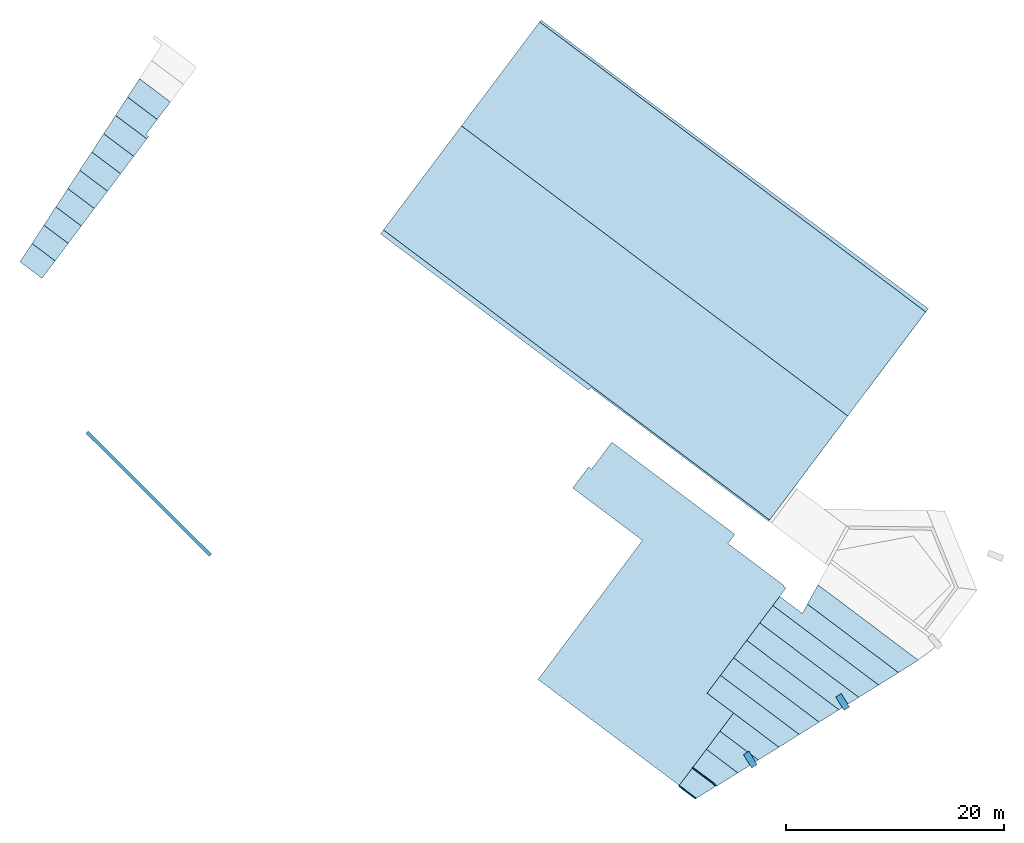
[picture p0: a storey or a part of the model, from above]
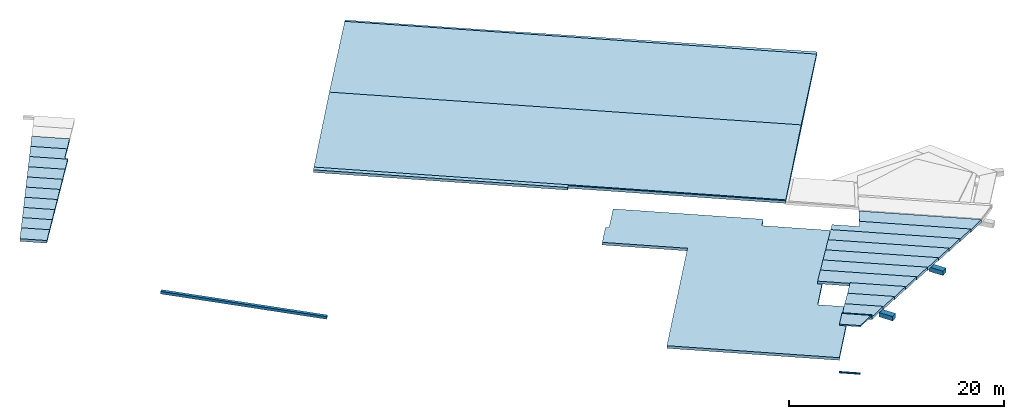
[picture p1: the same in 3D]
Properties of the parts of a building model (IFC2X3)

# File
Description: ViewDefinition [CoordinationView_V2.0], RevitIdentifiers [VersionGUID: fc82f88f-a926-4ae7-b725-2671d25d69d6, NumberOfSaves: 167], CoordinateReference [CoordinateBase: Coordenadas compartidas, ProjectSite: Interna]
File name: 0001
Time: 2024-03-04T15:58:45
Written by: ODA IFC SDK 22.8
Made in: 22.1.50.17 - Exporter 22.6.2.0 - IU alternativa 22.6.2.0

# IfcProject, 0001
LongName: TÍTOL DEL PROJECTE; Phase: Estado de proyecto

# IfcSite, Superficie:112586
RefLatitude: 40, 24, 0, 5493; RefLongitude: -3, -40, -59, -880065; RefElevation: 0 m

# IfcBuilding
Pset_BuildingCommon - NumberOfStoreys: 4

# IfcBuildingStorey: Nivel:A- Nivell (4)
Name | LongName | Elevation (m)
PS1- Gimnàs | PS1- Gimnàs | -5.45
PS1- Vestuari | PS1- Vestuari | -4.46
P0- Escola | P0- Escola | 0
PC- Coberta STR | PC- Coberta STR | 3.4

# IfcBuildingElementProxy: PerfilVoltant:PerfilVoltant (2)
In: P0- Escola
Type - Material: <Unnamed>
Pset_BuildingElementProxyCommon - Reference: PerfilVoltant; sets with these values: 2
Name (PerfilVoltant:PerfilVoltant:...)
849642
887236

# IfcColumn: STR- P- Acer- RHS- Rectangular- T1:45 x 25RHS (7)
In: P0- Escola
Type - PredefinedType: COLUMN; Material: Metal - Acero - 345 MPa
Type - Pset_ColumnCommon - IsExternal: no; LoadBearing: yes
Pset_ColumnCommon - Reference: 45 x 25RHS
Pset_QuantityTakeOff - Reference: 45 x 25RHS; sets with these values: 2
Name (STR- P- Acer- RHS- Rectangular- T1:45 x 25RHS:...)
849639
849651
849653
849655
886750
886810
886834

# IfcCurtainWall: Muro cortina:SER EXT- Tanca exterior (46)
Type - Pset_CurtainWallCommon - IsExternal: yes
Pset_CurtainWallCommon - Reference: SER EXT- Tanca exterior
Pset_QuantityTakeOff - Reference: SER EXT- Tanca exterior
Name (Muro cortina:SER EXT- Tanca exterior:...) | In
178892 | P0- Escola
178897 | P0- Escola
178907 | P0- Escola
178912 | P0- Escola
219770 | P0- Escola
220218 | P0- Escola
220369 | P0- Escola
220476 | P0- Escola
220625 | P0- Escola
220727 | P0- Escola
220855 | P0- Escola
220986 | P0- Escola
221199 | P0- Escola
221353 | P0- Escola
221500 | P0- Escola
221639 | P0- Escola
221781 | P0- Escola
221917 | P0- Escola
222063 | P0- Escola
222252 | P0- Escola
222425 | P0- Escola
222799 | PC- Coberta STR
222915 | PC- Coberta STR
223154 | PC- Coberta STR
223494 | P0- Escola
223676 | P0- Escola
223843 | P0- Escola
223951 | P0- Escola
224065 | P0- Escola
224211 | P0- Escola
224432 | PC- Coberta STR
226283 | PS1- Vestuari
226287 | PS1- Vestuari
226291 | PS1- Vestuari
226295 | PS1- Vestuari
226299 | PS1- Vestuari
226303 | PS1- Vestuari
226307 | PS1- Vestuari
226311 | PS1- Vestuari
226315 | PS1- Vestuari
242768 | PC- Coberta STR
243418 | PC- Coberta STR
243803 | PC- Coberta STR
249298 | P0- Escola
258339 | PS1- Vestuari
825201 | P0- Escola

# IfcDoor: SER EXT- SG2- Abatible- Ext:SER- EXT- SG2- Abatible- Ext- 1.98m (2)
In: PS1- Vestuari
Type - ParameterTakesPrecedence: no; Sizeable: no; Material: <Unnamed>
Type - Pset_DoorCommon - IsExternal: no
OverallHeight: 5.045 m; OverallWidth: 1.2275 m
Pset_DoorCommon - Reference: SER- EXT- SG2- Abatible- Ext- 1.98m
Pset_QuantityTakeOff - Reference: SER- EXT- SG2- Abatible- Ext- 1.98m
Name (SER EXT- SG2- Abatible- Ext:SER- EXT- SG2- Abatible- Ext- 1.98m:...)
884023
971733

# IfcDoor: SER EXT- SG2- Abatible- Ext:SER- EXT- SG2- Abatible- Ext- 2.15m, SER EXT- SG2- Abatible- Ext:SER- EXT- SG2- Abatible- Ext- 2.15m:849643
In: PS1- Vestuari
Type - ParameterTakesPrecedence: no; Sizeable: no; Material: <Unnamed>
Type - Pset_DoorCommon - IsExternal: no
OverallHeight: 5.215 m; OverallWidth: 1.42 m
Pset_DoorCommon - Reference: SER- EXT- SG2- Abatible- Ext- 2.15m
Pset_QuantityTakeOff - Reference: SER- EXT- SG2- Abatible- Ext- 2.15m

# IfcDoor: SER EXT- SG2- Abatible- Int:SER- EXT- SG2- Abatible ext - 1.98m (2)
In: P0- Escola
Type - ParameterTakesPrecedence: no; Sizeable: no; Material: <Unnamed>
Type - Pset_DoorCommon - IsExternal: no
OverallHeight: 5.63 m; OverallWidth: 1.1575 m
Pset_DoorCommon - Reference: SER- EXT- SG2- Abatible ext - 1.98m
Pset_QuantityTakeOff - Reference: SER- EXT- SG2- Abatible ext - 1.98m
Name (SER EXT- SG2- Abatible- Int:SER- EXT- SG2- Abatible ext - 1.98m:...)
877908
971731

# IfcDoor: SER EXT- SG2- Abatible- Int:SER- EXT- SG2- Abatible ext 2.15m, SER EXT- SG2- Abatible- Int:SER- EXT- SG2- Abatible ext 2.15m:849644
In: PS1- Vestuari
Type - ParameterTakesPrecedence: no; Sizeable: no; Material: <Unnamed>
Type - Pset_DoorCommon - IsExternal: no
OverallHeight: 5.8 m; OverallWidth: 1.35 m
Pset_DoorCommon - Reference: SER- EXT- SG2- Abatible ext 2.15m
Pset_QuantityTakeOff - Reference: SER- EXT- SG2- Abatible ext 2.15m

# IfcDoor: SER EXT- SG2- FIXE:SER- EXT- SG2- FIXE- 2.15m (2)
In: PS1- Vestuari
Type - ParameterTakesPrecedence: no; Sizeable: no; Material: <Unnamed>
Type - Pset_DoorCommon - IsExternal: no
OverallHeight: 2.14 m
Pset_DoorCommon - Reference: SER- EXT- SG2- FIXE- 2.15m
Pset_QuantityTakeOff - Reference: SER- EXT- SG2- FIXE- 2.15m
Name (SER EXT- SG2- FIXE:SER- EXT- SG2- FIXE- 2.15m:...) | OverallWidth (m)
849638 | 1
849650 | 1.024

# IfcDoor: SER URB- SM1a- PORTA ACCES ESCOLA:SER URB- SM1a- PORTA ACCES ESCOLA, SER URB- SM1a- PORTA ACCES ESCOLA:SER URB- SM1a- PORTA ACCES ESCOLA:906945
In: P0- Escola
Type - ParameterTakesPrecedence: no; Sizeable: no; Material: <Unnamed>
Type - Pset_DoorCommon - IsExternal: no
OverallHeight: 5.1 m; OverallWidth: 5.04225 m
Pset_DoorCommon - IsExternal: yes; Reference: SER URB- SM1a- PORTA ACCES ESCOLA
Pset_QuantityTakeOff - Reference: SER URB- SM1a- PORTA ACCES ESCOLA

# IfcDoor: SER URB- SM1b- FIXE OPACA:SER URB- SM1b- FIXE OPACA, SER URB- SM1b- FIXE OPACA:SER URB- SM1b- FIXE OPACA:909046
In: P0- Escola
Type - ParameterTakesPrecedence: no; Sizeable: no; Material: <Unnamed>
Type - Pset_DoorCommon - IsExternal: no
OverallHeight: 5 m; OverallWidth: 0.405 m
Pset_DoorCommon - IsExternal: yes; Reference: SER URB- SM1b- FIXE OPACA
Pset_QuantityTakeOff - Reference: SER URB- SM1b- FIXE OPACA

# IfcDoor: SER URB- SM1b- PORTA PETITA ACCES ESCOLA:SER URB- SM1b- PORTA PETITA ACCES ESCOLA, SER URB- SM1b- PORTA PETITA ACCES ESCOLA:SER URB- SM1b- PORTA PETITA ACCES ESCOLA:911182
In: PS1- Vestuari
Type - ParameterTakesPrecedence: no; Sizeable: no; Material: <Unnamed>
Type - Pset_DoorCommon - IsExternal: no
OverallHeight: 5 m; OverallWidth: 1.32329 m
Pset_DoorCommon - IsExternal: yes; Reference: SER URB- SM1b- PORTA PETITA ACCES ESCOLA
Pset_QuantityTakeOff - Reference: SER URB- SM1b- PORTA PETITA ACCES ESCOLA

# IfcDoor: SER URB- SM3- PORTA ACCES ESCOLA INFERIOR:SER URB- SM3- PORTA ACCES ESCOLA INFERIOR, SER URB- SM3- PORTA ACCES ESCOLA INFERIOR:SER URB- SM3- PORTA ACCES ESCOLA INFERIOR:841666
In: P0- Escola
Type - ParameterTakesPrecedence: no; Sizeable: no; Material: <Unnamed>
Type - Pset_DoorCommon - IsExternal: no
OverallHeight: 4.95 m; OverallWidth: 5.04225 m
Pset_DoorCommon - Reference: SER URB- SM3- PORTA ACCES ESCOLA INFERIOR
Pset_QuantityTakeOff - Reference: SER URB- SM3- PORTA ACCES ESCOLA INFERIOR

# IfcMember: Montante circular:Perfil Tanca exterior (158)
Type - PredefinedType: MULLION; Material: Acero inoxidable
Type - Pset_MemberCommon - IsExternal: no
Pset_MemberCommon - Reference: Perfil Tanca exterior
Pset_QuantityTakeOff - Reference: Perfil Tanca exterior
Name (Montante circular:Perfil Tanca exterior:...) | In | Span (m)
218592 | P0- Escola | 2 | Pset_MemberCommon - IsExternal: yes
224694 | P0- Escola | 2 | Pset_MemberCommon - IsExternal: yes
246355 | P0- Escola | 2 | Pset_MemberCommon - IsExternal: yes
213103 | P0- Escola | 2.01067
213405 | P0- Escola | 2.01067
213406 | P0- Escola | 1.95
213432 | P0- Escola | 2.01188
213433 | P0- Escola | 1.95
213464 | P0- Escola | 2.01188
213465 | P0- Escola | 1.95
213486 | P0- Escola | 2.01024
213487 | P0- Escola | 1.95
224695 | P0- Escola | 1.95
246356 | P0- Escola | 2
226271 | P0- Escola | 2
246358 | P0- Escola | 2
226239 | P0- Escola | 2
226240 | P0- Escola | 2
226241 | P0- Escola | 2
226242 | P0- Escola | 2
226243 | P0- Escola | 2
226244 | P0- Escola | 2
226245 | P0- Escola | 2
219928 | P0- Escola | 2
224699 | P0- Escola | 2
246362 | P0- Escola | 2
224700 | P0- Escola | 2
226535 | P0- Escola | 2
246363 | P0- Escola | 2.05
224701 | P0- Escola | 2
226584 | P0- Escola | 2
246364 | P0- Escola | 2
224702 | P0- Escola | 2
226633 | P0- Escola | 2
246365 | P0- Escola | 2
224703 | P0- Escola | 2
226698 | P0- Escola | 2
246366 | P0- Escola | 2
224704 | P0- Escola | 2
226775 | P0- Escola | 2
246367 | P0- Escola | 2.05
224705 | P0- Escola | 2
226870 | P0- Escola | 2
224706 | P0- Escola | 2
226957 | P0- Escola | 2
246369 | P0- Escola | 2.05
224707 | P0- Escola | 2
227058 | P0- Escola | 2
246370 | P0- Escola | 2.05
224708 | P0- Escola | 2
227159 | P0- Escola | 2
246371 | P0- Escola | 2.05
224709 | P0- Escola | 2
227236 | P0- Escola | 2
246372 | P0- Escola | 2.05
224710 | P0- Escola | 2
227293 | P0- Escola | 2
246373 | P0- Escola | 2.05
224711 | P0- Escola | 2
227364 | P0- Escola | 2
246374 | P0- Escola | 2.05
224712 | P0- Escola | 2
227481 | P0- Escola | 2
246375 | P0- Escola | 2.05
224713 | P0- Escola | 2
227568 | P0- Escola | 2
246376 | P0- Escola | 2.05
224714 | P0- Escola | 2
227621 | P0- Escola | 2
246377 | P0- Escola | 2.05
224715 | P0- Escola | 2
227748 | P0- Escola | 2
246378 | P0- Escola | 2
224716 | PC- Coberta STR | 2.05
225268 | PC- Coberta STR | 2
246379 | PC- Coberta STR | 2
224717 | PC- Coberta STR | 2.05
225345 | PC- Coberta STR | 2
246380 | PC- Coberta STR | 2
224718 | PC- Coberta STR | 2.05
225448 | PC- Coberta STR | 2
246381 | PC- Coberta STR | 2
224719 | P0- Escola | 2
225774 | P0- Escola | 2
246382 | P0- Escola | 2
224720 | P0- Escola | 2.05
225825 | P0- Escola | 2
246383 | P0- Escola | 2
224721 | P0- Escola | 2.05
225894 | P0- Escola | 2
246384 | P0- Escola | 2
224722 | P0- Escola | 2.05
225967 | P0- Escola | 2
246385 | P0- Escola | 2
224723 | P0- Escola | 2.05
226010 | P0- Escola | 2
246386 | P0- Escola | 2
224724 | P0- Escola | 2.05
226113 | P0- Escola | 2
226152 | P0- Escola | 2
246387 | P0- Escola | 2
224874 | PC- Coberta STR | 2
225174 | PC- Coberta STR | 2
830094 | PC- Coberta STR | 2
260684 | PS1- Vestuari | 2
260866 | PS1- Vestuari | 2
260974 | PS1- Vestuari | 2
261100 | PS1- Vestuari | 2
261216 | PS1- Vestuari | 2
261318 | PS1- Vestuari | 2
261446 | PS1- Vestuari | 2
261809 | PS1- Vestuari | 2
262452 | PS1- Vestuari | 2
259919 | PS1- Vestuari | 2
260018 | PS1- Vestuari | 2
260059 | PS1- Vestuari | 2
260165 | PS1- Vestuari | 2
260259 | PS1- Vestuari | 2
260317 | PS1- Vestuari | 2
260550 | PS1- Vestuari | 2
226432 | PS1- Vestuari | 2
259739 | PS1- Vestuari | 2
261954 | PS1- Vestuari | 2
226433 | PS1- Vestuari | 2.05
259070 | PS1- Vestuari | 2
259186 | PS1- Vestuari | 2
259493 | PS1- Vestuari | 2
259601 | PS1- Vestuari | 2
226434 | PS1- Vestuari | 2
246392 | PS1- Vestuari | 2.05
226435 | PS1- Vestuari | 2.05
258709 | PS1- Vestuari | 2
258770 | PS1- Vestuari | 2
226436 | PS1- Vestuari | 2
246394 | PS1- Vestuari | 2
226437 | PS1- Vestuari | 2
242773 | PC- Coberta STR | 2
244245 | PC- Coberta STR | 2
244415 | PC- Coberta STR | 2
246397 | PC- Coberta STR | 2
243421 | PC- Coberta STR | 2.05
244627 | PC- Coberta STR | 2
244905 | PC- Coberta STR | 2
245248 | PC- Coberta STR | 2
245395 | PC- Coberta STR | 2
246398 | PC- Coberta STR | 2
243806 | PC- Coberta STR | 2.05
245706 | PC- Coberta STR | 2
245858 | PC- Coberta STR | 2
246123 | PC- Coberta STR | 2
249302 | P0- Escola | 2
249303 | P0- Escola | 2
249627 | P0- Escola | 2
249694 | P0- Escola | 2
258342 | PS1- Vestuari | 2
258343 | PS1- Vestuari | 2
825320 | P0- Escola | 2
825321 | P0- Escola | 2.05

# IfcMember: Montante rectangular:Montante rectangular 100x50 (121)
Type - PredefinedType: MULLION; Material: _Formigó- Solera- T1- STR
Type - Pset_MemberCommon - IsExternal: no
Pset_MemberCommon - Reference: Montante rectangular 100x50
Pset_QuantityTakeOff - Reference: Montante rectangular 100x50
Name (Montante rectangular:Montante rectangular 100x50:...) | In | Span (m)
794372 | P0- Escola | 1.08514 | Pset_MemberCommon - IsExternal: yes
794373 | P0- Escola | 2.21752 | Pset_MemberCommon - IsExternal: yes
794374 | P0- Escola | 1.96448
794375 | P0- Escola | 2.01454
794376 | P0- Escola | 2.01454
794377 | P0- Escola | 2.0129
794378 | P0- Escola | 2.012
794380 | P0- Escola | 2.03155
794381 | P0- Escola | 1.98418
794382 | P0- Escola | 1.98668
794383 | P0- Escola | 1.98668
794384 | P0- Escola | 1.98668
794385 | P0- Escola | 1.98668
794386 | P0- Escola | 1.98668
794387 | P0- Escola | 1.98644
794388 | P0- Escola | 1.60597
794389 | P0- Escola | 2
794390 | P0- Escola | 2.05
794391 | P0- Escola | 1.95
794392 | P0- Escola | 2.05
794393 | P0- Escola | 2
794394 | P0- Escola | 2.05
794395 | P0- Escola | 2
794396 | P0- Escola | 2.05
794397 | P0- Escola | 2
794398 | P0- Escola | 2.05
794399 | P0- Escola | 1.95
794400 | P0- Escola | 2
794401 | P0- Escola | 2
794402 | P0- Escola | 2.05
794403 | P0- Escola | 1.95
794404 | P0- Escola | 2.05
794405 | P0- Escola | 1.95
794406 | P0- Escola | 2.05
794407 | P0- Escola | 1.95
794408 | P0- Escola | 2.05
794409 | P0- Escola | 1.95
794410 | P0- Escola | 2.05
794411 | P0- Escola | 1.95
794412 | P0- Escola | 2.05
794413 | P0- Escola | 1.95
794414 | P0- Escola | 2.05
794415 | P0- Escola | 1.95
794416 | P0- Escola | 2.05
794417 | P0- Escola | 1.95
794418 | P0- Escola | 2.05
794419 | P0- Escola | 1.95
794420 | P0- Escola | 2.05
794421 | P0- Escola | 3.18127
794422 | P0- Escola | 2.05
794423 | PC- Coberta STR | 2.05
794424 | PC- Coberta STR | 1.95
794425 | PC- Coberta STR | 2.05
794426 | PC- Coberta STR | 1.95
794427 | PC- Coberta STR | 2
794428 | PC- Coberta STR | 1.95
794429 | P0- Escola | 2.05
794430 | P0- Escola | 2
794431 | P0- Escola | 2.05
794432 | P0- Escola | 1.95
794433 | P0- Escola | 2.05
794434 | P0- Escola | 1.95
794435 | P0- Escola | 2.05
794436 | P0- Escola | 1.95
794437 | P0- Escola | 2.05
794438 | P0- Escola | 1.95
794439 | P0- Escola | 2
794440 | P0- Escola | 1.95
794441 | P0- Escola | 2
794442 | PC- Coberta STR | 2.42351
794443 | PC- Coberta STR | 2.05
794444 | PS1- Vestuari | 0.381107
794445 | PS1- Vestuari | 0.350019
794446 | PS1- Vestuari | 2
794447 | PS1- Vestuari | 2
794448 | PS1- Vestuari | 2
794449 | PS1- Vestuari | 2
794450 | PS1- Vestuari | 2
794451 | PS1- Vestuari | 2
794452 | PS1- Vestuari | 2
794453 | PS1- Vestuari | 1.89214
794454 | PS1- Vestuari | 1.64287
794455 | PS1- Vestuari | 1.30014
794456 | PS1- Vestuari | 2
794457 | PS1- Vestuari | 2
794458 | PS1- Vestuari | 2
794459 | PS1- Vestuari | 2
794460 | PS1- Vestuari | 2
794461 | PS1- Vestuari | 2
794462 | PS1- Vestuari | 0.724806
794463 | PS1- Vestuari | 2
794464 | PS1- Vestuari | 2
794465 | PS1- Vestuari | 2.00295
794466 | PS1- Vestuari | 1.95
794467 | PS1- Vestuari | 2
794468 | PS1- Vestuari | 2
794469 | PS1- Vestuari | 2
794470 | PS1- Vestuari | 1.95034
794471 | PS1- Vestuari | 2.00034
794472 | PS1- Vestuari | 1.95
794473 | PS1- Vestuari | 2.0277
794474 | PS1- Vestuari | 2.00665
794475 | PS1- Vestuari | 2
794476 | PS1- Vestuari | 2
794477 | PC- Coberta STR | 2.00218
794478 | PC- Coberta STR | 2.05
794479 | PC- Coberta STR | 2
794480 | PC- Coberta STR | 2.02451
794481 | PC- Coberta STR | 1.95
794482 | PC- Coberta STR | 2
794483 | PC- Coberta STR | 2
794484 | PC- Coberta STR | 2
794485 | PC- Coberta STR | 0.975363
794486 | PC- Coberta STR | 1.95
794487 | PC- Coberta STR | 2
794488 | PC- Coberta STR | 2
794489 | P0- Escola | 2.0155
794490 | P0- Escola | 2.0155
794491 | P0- Escola | 2.02639
794493 | PS1- Vestuari | 2.03879
825319 | P0- Escola | 1.61378

# IfcRailing: Barandilla:BaranaEscalaBiblioteca_NomesBarana (3)
In: P0- Escola
Material: <Unnamed>
Pset_QuantityTakeOff - Reference: BaranaEscalaBiblioteca_NomesBarana
Pset_RailingCommon - IsExternal: no; Reference: BaranaEscalaBiblioteca_NomesBarana; Height: 0.81 m
Name (Barandilla:BaranaEscalaBiblioteca_NomesBarana:...)
417718
427256
427480

# IfcRailing: Barandilla:BaranaEscalaGimnas, Barandilla:BaranaEscalaGimnas:429829
In: P0- Escola
Material: <Unnamed>
Pset_QuantityTakeOff - Reference: BaranaEscalaGimnas
Pset_RailingCommon - IsExternal: no; Reference: BaranaEscalaGimnas; Height: 0.81 m

# IfcRailing: Barandilla:PassamansDoble_sWa1, Barandilla:PassamansDoble_sWa1:433244
In: P0- Escola
Material: <Unnamed>
Pset_QuantityTakeOff - Reference: PassamansDoble_sWa1
Pset_RailingCommon - IsExternal: no; Reference: PassamansDoble_sWa1; Height: 0.81 m

# IfcRailing: Barandilla:SER EXT- Barana biblioteca, Barandilla:SER EXT- Barana biblioteca:429284
In: P0- Escola
Material: <Unnamed>
Pset_QuantityTakeOff - Reference: SER EXT- Barana biblioteca
Pset_RailingCommon - IsExternal: no; Reference: SER EXT- Barana biblioteca; Height: 0.81 m

# IfcRailing: Barandilla:SER EXT- Barana pati infantil, Barandilla:SER EXT- Barana pati infantil:429043
In: P0- Escola
Material: <Unnamed>
Pset_QuantityTakeOff - Reference: SER EXT- Barana pati infantil
Pset_RailingCommon - IsExternal: no; Reference: SER EXT- Barana pati infantil; Height: 0.81 m

# IfcRailing: SER URB- SM1d- TANCA LATERAL GRAN:SER URB- SM1d- TANCA LATERAL GRAN, SER URB- SM1d- TANCA LATERAL GRAN:SER URB- SM1d- TANCA LATERAL GRAN:915583
In: P0- Escola
Type - Material: <Unnamed>
Type - Pset_RailingCommon - IsExternal: no
Pset_QuantityTakeOff - Reference: SER URB- SM1d- TANCA LATERAL GRAN
Pset_RailingCommon - IsExternal: yes; Reference: SER URB- SM1d- TANCA LATERAL GRAN

# IfcRailing: SER URB- SM1d- TANCA LATERAL PETITA CANTONADA:SER URB- SM1d- TANCA LATERAL PETITA CANTONADA, SER URB- SM1d- TANCA LATERAL PETITA CANTONADA:SER URB- SM1d- TANCA LATERAL PETITA CANTONADA:912986
In: P0- Escola
Type - Material: <Unnamed>
Type - Pset_RailingCommon - IsExternal: no
Pset_QuantityTakeOff - Reference: SER URB- SM1d- TANCA LATERAL PETITA CANTONADA
Pset_RailingCommon - IsExternal: yes; Reference: SER URB- SM1d- TANCA LATERAL PETITA CANTONADA

# IfcRoof: Cubierta básica:COB- Coberta Xapa 2 (2)
In: P0- Escola
Material: _REV- Xapa minionda 0.01 m, _Genèric perfils, muntants, rastrells 0.01 m, _Aillament 0.08 m
Pset_QuantityTakeOff - Reference: COB- Coberta Xapa 2
Pset_RoofCommon - IsExternal: yes; Reference: COB- Coberta Xapa 2
Name (Cubierta básica:COB- Coberta Xapa 2:...) | ProjectedArea (m2) | TotalArea (m2)
902991 | 6.10059 | 6.11156
903251 | 6.13022 | 6.14125

# IfcRoof: Cubierta básica:COB- Coberta Xapa Exterior, Cubierta básica:COB- Coberta Xapa Exterior:886697
In: P0- Escola
Material: _REV- Xapa minionda 0.01 m, _Genèric perfils, muntants, rastrells 0.01 m, _Aillament 0.04 m
Pset_QuantityTakeOff - Reference: COB- Coberta Xapa Exterior
Pset_RoofCommon - IsExternal: yes; Reference: COB- Coberta Xapa Exterior; ProjectedArea: 3.40161 m2; TotalArea: 3.40161 m2

# IfcSlab: Cubierta básica:COB- Coberta Xapa 2 (2)
In: P0- Escola
Type - PredefinedType: ROOF
Type - Pset_SlabCommon - IsExternal: yes; ThermalTransmittance: 2.49973 kg/K/s3
Material: _REV- Xapa minionda 0.01 m, _Genèric perfils, muntants, rastrells 0.01 m, _Aillament 0.08 m
Pset_QuantityTakeOff - Reference: COB- Coberta Xapa 2; sets with these values: 2
Pset_SlabCommon - Reference: COB- Coberta Xapa 2; PitchAngle: 3.43363 deg
Name (Cubierta básica:COB- Coberta Xapa 2:...)
902991
903251

# IfcSlab: Cubierta básica:COB- Coberta Xapa Exterior, Cubierta básica:COB- Coberta Xapa Exterior:886697
In: P0- Escola
Type - PredefinedType: ROOF
Type - Pset_SlabCommon - IsExternal: yes; ThermalTransmittance: 2.49973 kg/K/s3
Material: _REV- Xapa minionda 0.01 m, _Genèric perfils, muntants, rastrells 0.01 m, _Aillament 0.04 m
Pset_QuantityTakeOff - Reference: COB- Coberta Xapa Exterior; sets with these values: 2
Pset_SlabCommon - PitchAngle: 0 deg; Reference: COB- Coberta Xapa Exterior

# IfcSlab: Plataforma:300 mm (110)
Type - PredefinedType: FLOOR; Material: _Topografia- Plataformes 0.3 m
Type - Pset_SlabCommon - IsExternal: no; ThermalTransmittance: 2.79 kg/K/s3
Pset_QuantityTakeOff - Reference: 300 mm; sets with these values: 2
Pset_SlabCommon - Reference: 300 mm
Name (Plataforma:300 mm:...) | In | PitchAngle (deg)
112604 | PS1- Gimnàs | 0
112612 | PS1- Vestuari | 0
112616 | PS1- Gimnàs | 0
112622 | PS1- Gimnàs | 1.14576
112626 | PS1- Vestuari | 0
112634 | PS1- Vestuari | 0
112641 | PS1- Vestuari | 3.75745
112661 | PS1- Vestuari | 5.10682
112667 | PS1- Vestuari | 0
112715 | P0- Escola | 4.57392
112724 | PS1- Gimnàs | 4.57392
112733 | PS1- Gimnàs | 4.57392
112742 | PS1- Gimnàs | 4.57392
112751 | PS1- Gimnàs | 4.57392
112760 | PS1- Gimnàs | 4.57392
112769 | PS1- Gimnàs | 4.57392
112778 | PS1- Gimnàs | 4.57392
112787 | PS1- Gimnàs | 4.57392
112798 | PS1- Gimnàs | 4.57392
112951 | PS1- Gimnàs | 1.14576
112959 | PS1- Gimnàs | 4.57392
113110 | PS1- Vestuari | 0
113144 | PS1- Gimnàs | 1.14576
113154 | PS1- Gimnàs | 0
113319 | PS1- Gimnàs | 2.29061
113327 | PS1- Gimnàs | 2.29061
113335 | PS1- Gimnàs | 2.29061
113634 | PS1- Gimnàs | 4.57392
113643 | PS1- Gimnàs | 4.57392
113651 | PS1- Gimnàs | 4.57392
113658 | PS1- Gimnàs | 4.57392
113665 | PS1- Gimnàs | 4.57392
113672 | PS1- Gimnàs | 4.57392
113680 | PS1- Gimnàs | 4.57392
113688 | PS1- Gimnàs | 4.57392
113696 | PS1- Gimnàs | 4.57392
113704 | PS1- Gimnàs | 4.57392
113711 | PS1- Gimnàs | 4.57392
113719 | PS1- Gimnàs | 4.57392
113879 | PS1- Vestuari | 4.57392
113892 | PS1- Vestuari | 4.57392
113901 | PS1- Vestuari | 4.57392
113910 | PS1- Vestuari | 4.57392
113919 | PS1- Vestuari | 4.57392
113941 | P0- Escola | 0
113957 | P0- Escola | 0
113968 | P0- Escola | 0
114032 | PS1- Vestuari | 0
114047 | P0- Escola | 7.32777
114102 | P0- Escola | 1.43206
114382 | P0- Escola | 0
114419 | P0- Escola | 0
114427 | PS1- Vestuari | 0
114435 | P0- Escola | 0
114444 | P0- Escola | 0
114452 | P0- Escola | 0
114487 | PS1- Vestuari | 4.57361
114496 | PS1- Vestuari | 4.57392
114505 | PS1- Vestuari | 0.859372
114513 | PS1- Vestuari | 1.14576
114530 | PS1- Vestuari | 0
114538 | PS1- Vestuari | 25.5005
114556 | PS1- Vestuari | 0
114567 | PS1- Vestuari | 0
114583 | PS1- Vestuari | 0
114600 | PS1- Vestuari | 0
114621 | PS1- Vestuari | 0
114629 | PS1- Vestuari | 25.4496
114638 | PS1- Vestuari | 25.8881
114647 | PS1- Vestuari | 0
114655 | PS1- Vestuari | 25.8881
114664 | PS1- Vestuari | 0
114672 | P0- Escola | 0
114680 | P0- Escola | 0
114688 | P0- Escola | 0
114696 | P0- Escola | 0
429259 | P0- Escola | 0
433192 | PS1- Gimnàs | 0
436202 | P0- Escola | 0
437801 | P0- Escola | 0
437916 | P0- Escola | 0
438030 | P0- Escola | 0
438046 | P0- Escola | 0
438072 | P0- Escola | 0
438098 | P0- Escola | 0
438118 | P0- Escola | 0
438151 | P0- Escola | 0
438417 | PS1- Gimnàs | 0
438637 | PS1- Vestuari | 0
440489 | PS1- Vestuari | 0
622989 | P0- Escola | 0
623017 | P0- Escola | 0
623747 | P0- Escola | 1.08092
623801 | P0- Escola | 1.78991
624366 | P0- Escola | 0
624937 | P0- Escola | 1.78991
625013 | P0- Escola | 1.08092
625038 | P0- Escola | 0
625057 | P0- Escola | 1.78991
625118 | P0- Escola | 1.08092
625294 | P0- Escola | 0
625413 | P0- Escola | 1.34789
626050 | P0- Escola | 1.34789
626185 | P0- Escola | 0
627149 | P0- Escola | 0
628680 | P0- Escola | 4.01039
812884 | P0- Escola | 4.49797
813592 | P0- Escola | 2.32091
847177 | P0- Escola | 0
953251 | P0- Escola | 3.00519

# IfcSlab: STR- S- Formigó- Mp5:STR- S- Formigó- Mp5, STR- S- Formigó- Mp5:STR- S- Formigó- Mp5:119742
In: PS1- Vestuari
Type - PredefinedType: BASESLAB; Material: _Formigó- T1- STR
Type - Pset_SlabCommon - IsExternal: no
Pset_QuantityTakeOff - Reference: STR- S- Formigó- Mp5; sets with these values: 2
Pset_SlabCommon - Reference: STR- S- Formigó- Mp5

# IfcSlab: STR- Sabata- Unio sabata MP1:STR- Sabata- Unio sabata MP1, STR- Sabata- Unio sabata MP1:STR- Sabata- Unio sabata MP1:119833
In: PS1- Vestuari
Type - PredefinedType: BASESLAB; Material: _Formigó- T1- STR
Type - Pset_SlabCommon - IsExternal: no
Pset_QuantityTakeOff - Reference: STR- Sabata- Unio sabata MP1; sets with these values: 2
Pset_SlabCommon - Reference: STR- Sabata- Unio sabata MP1

# IfcSlab: STR- Sabata- Unio sabata MP2:STR- Sabata- Unio sabata MP1, STR- Sabata- Unio sabata MP2:STR- Sabata- Unio sabata MP1:119843
In: PS1- Gimnàs
Type - PredefinedType: BASESLAB; Material: _Formigó- T1- STR
Type - Pset_SlabCommon - IsExternal: no
Pset_QuantityTakeOff - Reference: STR- Sabata- Unio sabata MP1; sets with these values: 2
Pset_SlabCommon - Reference: STR- Sabata- Unio sabata MP1

# IfcSlab: STR- Sabata- Unio sabata MP3:STR- Sabata- Unio sabata MP1, STR- Sabata- Unio sabata MP3:STR- Sabata- Unio sabata MP1:119851
In: PS1- Gimnàs
Type - PredefinedType: BASESLAB; Material: _Formigó- T1- STR
Type - Pset_SlabCommon - IsExternal: no
Pset_QuantityTakeOff - Reference: STR- Sabata- Unio sabata MP1; sets with these values: 2
Pset_SlabCommon - Reference: STR- Sabata- Unio sabata MP1

# IfcSlab: STR- Sabata- Unio sabata MP4:STR- Sabata- Unio sabata MP1, STR- Sabata- Unio sabata MP4:STR- Sabata- Unio sabata MP1:119859
In: PS1- Gimnàs
Type - PredefinedType: BASESLAB; Material: _Formigó- T1- STR
Type - Pset_SlabCommon - IsExternal: no
Pset_QuantityTakeOff - Reference: STR- Sabata- Unio sabata MP1; sets with these values: 2
Pset_SlabCommon - Reference: STR- Sabata- Unio sabata MP1

# IfcSlab: STR- Sabata- Unio sabata MP5:STR- Sabata- Unio sabata MP1, STR- Sabata- Unio sabata MP5:STR- Sabata- Unio sabata MP1:119871
In: PS1- Gimnàs
Type - PredefinedType: BASESLAB; Material: _Formigó- T1- STR
Type - Pset_SlabCommon - IsExternal: no
Pset_QuantityTakeOff - Reference: STR- Sabata- Unio sabata MP1; sets with these values: 2
Pset_SlabCommon - Reference: STR- Sabata- Unio sabata MP1

# IfcSlab: Suelo:PAV- Saulo- 15 cm- T1 (3)
In: P0- Escola
Pset_QuantityTakeOff - Reference: PAV- Saulo- 15 cm- T1; sets with these values: 2
Pset_SlabCommon - IsExternal: no; LoadBearing: yes; Reference: PAV- Saulo- 15 cm- T1
Name (Suelo:PAV- Saulo- 15 cm- T1:...) | PitchAngle (deg)
114356 | 3.08047
742770 | 1.11631
844990 | 5.07385

# IfcSlab: Suelo:PAV- Saulo- 15 cm- T1 (64)
Type - PredefinedType: FLOOR; Material: _Saulo T1- PAV 0.15 m
Type - Pset_SlabCommon - IsExternal: no; ThermalTransmittance: 5.58 kg/K/s3
Pset_QuantityTakeOff - Reference: PAV- Saulo- 15 cm- T1; sets with these values: 2
Pset_SlabCommon - Reference: PAV- Saulo- 15 cm- T1
Name (Suelo:PAV- Saulo- 15 cm- T1:...) | In | LoadBearing | PitchAngle (deg)
113406 | PS1- Vestuari | no | 0.869827
113466 | P0- Escola | no | 4.57392 | Group: Grupo de modelo:PavimentPendent_01:113740
113480 | P0- Escola | no | 4.57392 | Group: Grupo de modelo:PavimentPendent_01:113740
113494 | P0- Escola | no | 4.57392 | Group: Grupo de modelo:PavimentPendent_01:113740
113508 | P0- Escola | no | 4.57392 | Group: Grupo de modelo:PavimentPendent_01:113740
113522 | P0- Escola | no | 4.57392 | Group: Grupo de modelo:PavimentPendent_01:113740
113536 | P0- Escola | no | 4.57392 | Group: Grupo de modelo:PavimentPendent_01:113740
113550 | P0- Escola | no | 4.57392 | Group: Grupo de modelo:PavimentPendent_01:113740
113564 | P0- Escola | no | 4.57392 | Group: Grupo de modelo:PavimentPendent_01:113740
113578 | P0- Escola | no | 4.57392 | Group: Grupo de modelo:PavimentPendent_01:113740
113592 | P0- Escola | no | 4.57392 | Group: Grupo de modelo:PavimentPendent_01:113740
113606 | P0- Escola | no | 4.57392 | Group: Grupo de modelo:PavimentPendent_01:113740
113620 | P0- Escola | no | 4.57392 | Group: Grupo de modelo:PavimentPendent_01:113740
113770 | P0- Escola | no | 4.57392
113781 | P0- Escola | no | 4.57392
113792 | P0- Escola | no | 4.57392
113803 | P0- Escola | no | 4.57392
113814 | P0- Escola | no | 4.57392
113935 | P0- Escola | no | 1.14576
113950 | P0- Escola | no | 1.11746
113998 | PS1- Vestuari | no | 5.10682
114072 | PS1- Vestuari | no | 1.43214
114138 | P0- Escola | no | 0
114177 | P0- Escola | no | 1.09448
114356 | P0- Escola | yes | 4.23795
114356 | P0- Escola | yes | 1.14576
114356 | P0- Escola | yes | 4.37787
114356 | P0- Escola | yes | 3.78611
114356 | P0- Escola | yes | 3.08047
114356 | P0- Escola | yes | 5.15186
114368 | P0- Escola | yes | 5.17448 | Material: _Saulo T1- PAV
435404 | P0- Escola | yes | 1.25967 | Material: _Saulo T1- PAV
742770 | P0- Escola | yes | 1.11631
742770 | P0- Escola | yes | 12.1707
742770 | P0- Escola | yes | 11.9335
742770 | P0- Escola | yes | 19.8422
844990 | P0- Escola | yes | 6.31766
844990 | P0- Escola | yes | 6.51825
844990 | P0- Escola | yes | 7.37769
844990 | P0- Escola | yes | 6.82529
844990 | P0- Escola | yes | 5.07385
844990 | P0- Escola | yes | 7.16385
844990 | P0- Escola | yes | 7.92568
844990 | P0- Escola | yes | 5.50607
844990 | P0- Escola | yes | 5.64288
844990 | P0- Escola | yes | 1.24268
844990 | P0- Escola | yes | 6.49366
844990 | P0- Escola | yes | 0.112977
845945 | PS1- Vestuari | no | 0
845948 | PS1- Vestuari | no | 5.10682
951018 | PS1- Gimnàs | yes | 4.57392 | Group: Grupo de modelo:Grupo 3:951125
951027 | P0- Escola | yes | 4.57392 | Group: Grupo de modelo:Grupo 3:951125
951037 | P0- Escola | yes | 4.57392 | Group: Grupo de modelo:Grupo 3:951125
951047 | P0- Escola | yes | 4.57392 | Group: Grupo de modelo:Grupo 3:951125
951057 | P0- Escola | yes | 4.57392 | Group: Grupo de modelo:Grupo 3:951125
951067 | P0- Escola | yes | 4.57392 | Group: Grupo de modelo:Grupo 3:951125
951077 | P0- Escola | yes | 4.57392 | Group: Grupo de modelo:Grupo 3:951125
951087 | P0- Escola | yes | 4.57392 | Group: Grupo de modelo:Grupo 3:951125
951097 | P0- Escola | yes | 4.57392 | Group: Grupo de modelo:Grupo 3:951125
951107 | P0- Escola | yes | 4.57392 | Group: Grupo de modelo:Grupo 3:951125
951118 | P0- Escola | yes | 4.57392 | Group: Grupo de modelo:Grupo 3:951125
951237 | PS1- Gimnàs | yes | 1.14576 | Group: Grupo de modelo:Grupo 3:951125
951255 | PS1- Gimnàs | yes | 1.14576 | Group: Grupo de modelo:Grupo 3:951125
951311 | P0- Escola | yes | 0 | Group: Grupo de modelo:Grupo 3:951125

# IfcSlab: Suelo:STR- L- Formigó- Solera- T1- 15 cm (43)
Type - PredefinedType: FLOOR; Material: _Formigó- Solera- T1- STR 0.15 m
Type - Pset_SlabCommon - IsExternal: no
Pset_QuantityTakeOff - Reference: STR- L- Formigó- Solera- T1- 15 cm; sets with these values: 2
Pset_SlabCommon - Reference: STR- L- Formigó- Solera- T1- 15 cm
Name (Suelo:STR- L- Formigó- Solera- T1- 15 cm:...) | In | LoadBearing | PitchAngle (deg) | Group
112925 | P0- Escola | yes | 1.14576
112935 | P0- Escola | yes | 1.14576
112976 | PS1- Gimnàs | no | 1.14576
113341 | P0- Escola | yes | 5.29487 | Material: _Formigó- Solera- T1- STR
113459 | P0- Escola | no | 4.57392 | Grupo de modelo:PavimentPendent_01:113740
113473 | P0- Escola | no | 4.57392 | Grupo de modelo:PavimentPendent_01:113740
113487 | P0- Escola | no | 4.57392 | Grupo de modelo:PavimentPendent_01:113740
113501 | P0- Escola | no | 4.57392 | Grupo de modelo:PavimentPendent_01:113740
113515 | P0- Escola | no | 4.57392 | Grupo de modelo:PavimentPendent_01:113740
113529 | P0- Escola | no | 4.57392 | Grupo de modelo:PavimentPendent_01:113740
113543 | P0- Escola | no | 4.57392 | Grupo de modelo:PavimentPendent_01:113740
113557 | P0- Escola | no | 4.57392 | Grupo de modelo:PavimentPendent_01:113740
113571 | P0- Escola | no | 4.57392 | Grupo de modelo:PavimentPendent_01:113740
113585 | P0- Escola | no | 4.57392 | Grupo de modelo:PavimentPendent_01:113740
113599 | P0- Escola | no | 4.57392 | Grupo de modelo:PavimentPendent_01:113740
113613 | P0- Escola | no | 4.57392 | Grupo de modelo:PavimentPendent_01:113740
113627 | P0- Escola | no | 0 | Grupo de modelo:PavimentPendent_01:113740
113823 | P0- Escola | no | 4.57392
113834 | P0- Escola | no | 4.57392
113845 | P0- Escola | no | 4.57392
113856 | P0- Escola | no | 4.57392
113867 | P0- Escola | no | 4.57392
114346 | P0- Escola | yes | 9.0795 | Material: _Formigó- Solera- T1- STR
114392 | P0- Escola | yes | 5.95549
697424 | P0- Escola | no | 4.49797
741639 | P0- Escola | no | 2.67602
742125 | P0- Escola | no | 2.32091
849610 | P0- Escola | no | 0
951128 | PS1- Gimnàs | yes | 4.57392 | Grupo de modelo:Grupo 3:951125
951136 | P0- Escola | yes | 4.57392 | Grupo de modelo:Grupo 3:951125
951146 | P0- Escola | yes | 4.57392 | Grupo de modelo:Grupo 3:951125
951156 | P0- Escola | yes | 4.57392 | Grupo de modelo:Grupo 3:951125
951166 | P0- Escola | yes | 4.57392 | Grupo de modelo:Grupo 3:951125
951176 | P0- Escola | yes | 4.57392 | Grupo de modelo:Grupo 3:951125
951186 | P0- Escola | yes | 4.57392 | Grupo de modelo:Grupo 3:951125
951196 | P0- Escola | yes | 4.57392 | Grupo de modelo:Grupo 3:951125
951206 | P0- Escola | yes | 4.57392 | Grupo de modelo:Grupo 3:951125
951216 | P0- Escola | yes | 4.57392 | Grupo de modelo:Grupo 3:951125
951227 | P0- Escola | yes | 4.57392 | Grupo de modelo:Grupo 3:951125
951246 | PS1- Gimnàs | yes | 0 | Grupo de modelo:Grupo 3:951125
951294 | PS1- Gimnàs | yes | 0 | Grupo de modelo:Grupo 3:951125
951304 | P0- Escola | no | 1.14576 | Grupo de modelo:Grupo 3:951125
953490 | P0- Escola | yes | 1.9854 | Material: _Formigó- Solera- T1- STR

# IfcSlab: Suelo:STR- L- Formigó- Solera- T1- 20 cm, Suelo:STR- L- Formigó- Solera- T1- 20 cm:113003
In: PS1- Gimnàs
Pset_QuantityTakeOff - Reference: STR- L- Formigó- Solera- T1- 20 cm; sets with these values: 2
Pset_SlabCommon - IsExternal: no; LoadBearing: no; Reference: STR- L- Formigó- Solera- T1- 20 cm; PitchAngle: 1.13856 deg

# IfcSlab: Suelo:STR- L- Formigó- Solera- T1- 20 cm (3)
Type - PredefinedType: FLOOR; Material: _Formigó- Solera- T1- STR 0.2 m
Type - Pset_SlabCommon - IsExternal: no
Pset_QuantityTakeOff - Reference: STR- L- Formigó- Solera- T1- 20 cm; sets with these values: 2
Pset_SlabCommon - Reference: STR- L- Formigó- Solera- T1- 20 cm
Name (Suelo:STR- L- Formigó- Solera- T1- 20 cm:...) | In | LoadBearing | PitchAngle (deg)
2 x 113003 | PS1- Gimnàs | no | 1.13856
114468 | P0- Escola | yes | 0.00119104

# IfcStair: Escalera moldeada in situ:E-X1- EscaleraRampa_01, Escalera moldeada in situ:Escalera:311998
In: P0- Escola
ShapeType: STRAIGHT_RUN_STAIR
Pset_QuantityTakeOff - Reference: E-X1- EscaleraRampa_01
Pset_StairCommon - IsExternal: yes; Reference: E-X1- EscaleraRampa_01; NumberOfRiser: 5; NumberOfTreads: 4; RiserHeight: 0.153 m; TreadLength: 0.3 m

# IfcStair: Escalera moldeada in situ:E-X1- EscaleraRampa_pecaFinal, Escalera moldeada in situ:Escalera:315003
In: P0- Escola
ShapeType: STRAIGHT_RUN_STAIR
Pset_QuantityTakeOff - Reference: E-X1- EscaleraRampa_pecaFinal
Pset_StairCommon - IsExternal: yes; Reference: E-X1- EscaleraRampa_pecaFinal; NumberOfRiser: 2; NumberOfTreads: 1; RiserHeight: 0.1815 m; TreadLength: 1.12 m

# IfcStairFlight: Tramo monolítico:E00- STR- ReplaFormigoFinal, Escalera moldeada in situ:Escalera:315003 Run 1
In: P0- Escola
Type - PredefinedType: STRAIGHT
NumberOfRiser: 2; NumberOfTreads: 1; RiserHeight: 0.595472 m; TreadLength: 3.67454 m; Material: _PAV escales STR
Pset_QuantityTakeOff - Reference: E00- STR- ReplaFormigoFinal
Pset_StairFlightCommon - NosingLength: 0 m; Reference: E00- STR- ReplaFormigoFinal; NumberOfRiser: 2; NumberOfTreads: 1; RiserHeight: 0.1815 m; TreadLength: 1.12 m; WalkingLineOffset: 2.46063 m; TreadLengthAtOffset: 1.12 m; TreadLengthAtInnerSide: 1.12 m

# IfcStairFlight: Tramo monolítico:E00- STR- ReplaFormigoInclinat, Escalera moldeada in situ:Escalera:311998 Run 1
In: P0- Escola
NumberOfRiser: 5; NumberOfTreads: 4; RiserHeight: 0.501969 m; TreadLength: 0.984252 m; Material: _PAV escales STR
Pset_QuantityTakeOff - Reference: E00- STR- ReplaFormigoInclinat
Pset_StairFlightCommon - Reference: E00- STR- ReplaFormigoInclinat; NumberOfRiser: 5; NumberOfTreads: 4; RiserHeight: 0.153 m; TreadLength: 0.3 m; NosingLength: 0 m; TreadLengthAtOffset: 0.3 m; TreadLengthAtInnerSide: 0.3 m

# IfcWall: Muro básico:ENV- Ceràmic- 14 cm, Muro básico:ENV- Ceràmic- 14 cm:877514
In: P0- Escola
Type - PredefinedType: STANDARD; Material: _Ceràmica- ENV 0.14 m
Type - Pset_WallCommon - IsExternal: yes
Pset_QuantityTakeOff - Reference: ENV- Ceràmic- 14 cm; sets with these values: 2
Pset_WallCommon - LoadBearing: no; ExtendToStructure: no; Reference: ENV- Ceràmic- 14 cm

# IfcWallStandardCase: Muro básico:ENV- Ceràmic- 14 cm (2)
In: P0- Escola
Type - PredefinedType: STANDARD; Material: _Ceràmica- ENV 0.14 m
Type - Pset_WallCommon - IsExternal: yes
Pset_QuantityTakeOff - Reference: ENV- Ceràmic- 14 cm; sets with these values: 2
Pset_WallCommon - LoadBearing: no; ExtendToStructure: no; Reference: ENV- Ceràmic- 14 cm
Name (Muro básico:ENV- Ceràmic- 14 cm:...)
877048
877379

# IfcWallStandardCase: Muro básico:STR- M- Formigó- Genèric- T1- 30 cm, Muro básico:STR- M- Formigó- Genèric- T1- 30 cm:114378
In: P0- Escola
Type - PredefinedType: STANDARD; Material: _Formigó- T1- STR 0.3 m
Type - Pset_WallCommon - IsExternal: yes
Pset_QuantityTakeOff - Reference: STR- M- Formigó- Genèric- T1- 30 cm; sets with these values: 2
Pset_WallCommon - LoadBearing: no; Reference: STR- M- Formigó- Genèric- T1- 30 cm; ExtendToStructure: no
